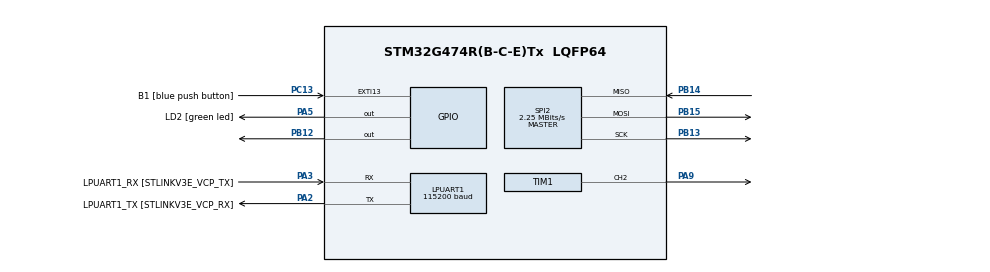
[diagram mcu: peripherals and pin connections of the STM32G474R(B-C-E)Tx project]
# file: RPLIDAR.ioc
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FATFS._MAX_SS=4096
FATFS._USE_LFN=1
LPUART1.BaudRate=115200
LPUART1.WordLength=UART_WORDLENGTH_8B
Mcu.Family=STM32G4
Mcu.Name=STM32G474R(B-C-E)Tx
Mcu.Package=LQFP64
NVIC.EXTI15_10_IRQn=true\:0\:0\:false\:false\:true\:true\:true
NVIC.PriorityGroup=NVIC_PRIORITYGROUP_4
PA13.GPIO_Label=T_SWDIO
PA13.Mode=Serial_Wire
PA13.Signal=SYS_JTMS-SWDIO
PA14.GPIO_Label=T_SWCLK
PA14.Mode=Serial_Wire
PA14.Signal=SYS_JTCK-SWCLK
PA2.GPIO_Label=LPUART1_TX [STLINKV3E_VCP_RX]
PA2.Mode=Asynchronous
PA2.Signal=LPUART1_TX
PA3.GPIO_Label=LPUART1_RX [STLINKV3E_VCP_TX]
PA3.Mode=Asynchronous
PA3.Signal=LPUART1_RX
PA5.GPIO_Label=LD2 [green led]
PA5.Signal=GPIO_Output
PA9.Signal=S_TIM1_CH2
PB12.Signal=GPIO_Output
PB13.Mode=Full_Duplex_Master
PB13.Signal=SPI2_SCK
PB14.Mode=Full_Duplex_Master
PB14.Signal=SPI2_MISO
PB15.Mode=Full_Duplex_Master
PB15.Signal=SPI2_MOSI
PB3.GPIO_Label=T_SWO
PB3.Signal=SYS_JTDO-SWO
PC13.GPIO_Label=B1 [blue push button]
PC13.Signal=GPXTI13
PC14-OSC32_IN.Mode=LSE-External-Oscillator
PC14-OSC32_IN.Signal=RCC_OSC32_IN
PC15-OSC32_OUT.Mode=LSE-External-Oscillator
PC15-OSC32_OUT.Signal=RCC_OSC32_OUT
PF0-OSC_IN.Mode=HSE-External-Oscillator
PF0-OSC_IN.Signal=RCC_OSC_IN
PF1-OSC_OUT.Mode=HSE-External-Oscillator
PF1-OSC_OUT.Signal=RCC_OSC_OUT
ProjectManager.HeapSize=0x200
ProjectManager.StackSize=0x400
ProjectManager.TargetToolchain=STM32CubeIDE
RCC.ADC12Freq_Value=144000000
RCC.ADC345Freq_Value=144000000
RCC.AHBFreq_Value=144000000
RCC.APB1Freq_Value=144000000
RCC.APB1TimFreq_Value=144000000
RCC.APB2Freq_Value=144000000
RCC.APB2TimFreq_Value=144000000
RCC.CortexFreq_Value=144000000
RCC.EXTERNAL_CLOCK_VALUE=12288000
RCC.HCLKFreq_Value=144000000
RCC.HSE_VALUE=24000000
RCC.HSI48_VALUE=48000000
RCC.HSI_VALUE=16000000
RCC.PLLN=18
RCC.RTCClockSelection=RCC_RTCCLKSOURCE_LSE
RCC.SYSCLKFreq_VALUE=144000000
RCC.SYSCLKSource=RCC_SYSCLKSOURCE_PLLCLK
RCC.USBFreq_Value=144000000
RCC.VCOOutputFreq_Value=288000000
SH.S_TIM1_CH2.0=TIM1_CH2,PWM Generation2 CH2
SPI2.BaudRatePrescaler=SPI_BAUDRATEPRESCALER_64
SPI2.CalculateBaudRate=2.25 MBits/s
SPI2.DataSize=SPI_DATASIZE_8BIT
SPI2.Direction=SPI_DIRECTION_2LINES
SPI2.Mode=SPI_MODE_MASTER
SPI2.VirtualType=VM_MASTER
TIM1.AutoReloadPreload=TIM_AUTORELOAD_PRELOAD_ENABLE
TIM1.Channel-PWM\ Generation2\ CH2=TIM_CHANNEL_2
TIM1.PeriodNoDither=5760-1
VP_FATFS_VS_Generic.Mode=User_defined
VP_SYS_VS_DBSignals.Mode=DisableDeadBatterySignals
VP_TIM1_VS_ClockSourceINT.Mode=Internal
board=NUCLEO-G474RE

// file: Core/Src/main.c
/* USER CODE BEGIN Header */
/**
  ******************************************************************************
  * @file           : main.c
  * @brief          : Main program body
  ******************************************************************************
  * @attention
  *
  * Copyright (c) 2022 STMicroelectronics.
  * All rights reserved.
  *
  * This software is licensed under terms that can be found in the LICENSE file
  * in the root directory of this software component.
  * If no LICENSE file comes with this software, it is provided AS-IS.
  *
  ******************************************************************************
  */
/* USER CODE END Header */
#include "main.h"
#include "app_fatfs.h"

/* USER CODE BEGIN Includes */
#include "math.h"
#include "uart_buf_g4.h"
/* USER CODE END Includes */

/* USER CODE BEGIN PD */
/*Comandos*/
#define STOP_RPL            0x25
#define RESET_RPL           0x40
#define SCAN_RPL            0x20
#define EXPRESS_SCAN_RPL    0x82
#define FORCE_SCAN_RPL      0x21
#define GET_INFO_RPL        0x50
#define GET_HEALTH_RPL      0x52
#define GET_SAMPLERATE_RPL  0x59
#define GET_LIDAR_CONF_RPL  0x84
/*StarFlags*/
#define START_FLAG_1         0xA5
#define START_FLAG_2         0x5A
/*Tamaños del buffer*/
#define  RxBuf_SIZE 		10
#define  MainBuf_SIZE 		(2<<14)//13->8192 14->16384 16->65536
#define precision 6  //precision for decimal digits
/* USER CODE END PD */

UART_HandleTypeDef hlpuart1;

SPI_HandleTypeDef hspi2;

TIM_HandleTypeDef htim1;

/* USER CODE BEGIN PV */
__IO ITStatus UserButtonStatus = 0;  /* set to 1 after User Button interrupt  */
uint8_t RxBuf[RxBuf_SIZE];
uint8_t MainBuf[MainBuf_SIZE];
const uint8_t STOP_REQUEST[2]={START_FLAG_1,STOP_RPL};
const uint8_t RESET_REQUEST[2]={START_FLAG_1,RESET_RPL};
const uint8_t SCAN_REQUEST[2]={START_FLAG_1,SCAN_RPL};
const uint8_t SCAN_DESCRIPTOR[7]={START_FLAG_1,START_FLAG_2,0x05,0x00,0x00,0x40,0x81};
const uint8_t GET_HEALTH_REQUEST[2]={START_FLAG_1,GET_HEALTH_RPL};
const uint8_t GET_HEALTH_DESCRIPTOR[7]={START_FLAG_1,START_FLAG_2,0x03,0x00,0x00,0x00,0x06};
const uint8_t GET_INFO_REQUEST[2]={START_FLAG_1,GET_INFO_RPL};
const uint8_t GET_INFO_DESCRIPTOR[7]={START_FLAG_1,START_FLAG_2,0x4,0x00,0x00,0x00,0x04};
const uint8_t EXPRESS_SCAN_REQUEST[7]={START_FLAG_1,EXPRESS_SCAN_RPL};

const uint8_t FORCE_SCAN_REQUEST[7]={START_FLAG_1,FORCE_SCAN_RPL};

/* USER CODE END PV */

void SystemClock_Config(void);
static void MX_GPIO_Init(void);
static void MX_LPUART1_UART_Init(void);
static void MX_SPI2_Init(void);
static void MX_TIM1_Init(void);
/* USER CODE BEGIN PFP */
void HAL_GPIO_EXTI_Callback(uint16_t GPIO_Pin)
{
  if (GPIO_Pin == GPIO_PIN_13)
  {
    UserButtonStatus = 1;
  }
}
uint8_t  BinToAsc(uint8_t  BinValue)
{
    BinValue &= 0x0F;
    if(BinValue > 9) BinValue += 7;
    return(BinValue + '0');
}
// Reverses a string 'str' of length 'len'
void reverse(char* str, int len)
{
    int i = 0, j = len - 1, temp;
    while (i < j) {
        temp = str[i];
        str[i] = str[j];
        str[j] = temp;
        i++;
        j--;
    }
}
// Converts a given integer x to string str[].
// d is the number of digits required in the output.
// If d is more than the number of digits in x,
// then 0s are added at the beginning.
int intToStr(int x, char str[], int d)
{
    int i = 0;
    while (x) {
        str[i++] = (x % 10) + '0';
        x = x / 10;
    }
    // If number of digits required is more, then
    // add 0s at the beginning
    while (i < d)
        str[i++] = '0';

    reverse(str, i);
    str[i] = '\0';
    return i;
}
// Converts a floating-point/double number to a string.
void ftoa(float n, char* res, int beforepoint,int afterpoint)
{
    // Extract integer part
    int ipart = (int)n;

    // Extract floating part
    float fpart = n - (float)ipart;

    // convert integer part to string
    int i = intToStr(ipart, res, beforepoint);

    // check for display option after point
    if (afterpoint != 0) {
        res[i] = '.'; // add dot

        // Get the value of fraction part upto given no.
        // of points after dot. The third parameter
        // is needed to handle cases like 233.007
        fpart = fpart * (float)(pow(10, afterpoint));

        intToStr((int)fpart, res + i + 1, afterpoint);
    }
}
void float_to_char(float f, char *p) {
	int a,b,c,k,l=0,m,i=0;
	// check for negetive float
	if(f<0.0)
	{
		p[i++]='-';
		f*=-1;
	}
	a=f;	// extracting whole number
	f-=a;	// extracting decimal part
	k = precision;
	// number of digits in whole number
	while(k>-1)
	{
		l = pow(10,k);
		m = a/l;
		if(m>0)
		{
			break;
		}
	k--;
	}
	// number of digits in whole number are k+1
	/*
	extracting most significant digit i.e. right most digit , and concatenating to string
	obtained as quotient by dividing number by 10^k where k = (number of digit -1)
	*/
	for(l=k+1;l>0;l--)
	{
		b = pow(10,l-1);
		c = a/b;
		p[i++]=c+48;
		a%=b;
	}
	p[i++] = '.';
	/* extracting decimal digits till precision */
	for(l=0;l<precision;l++)
	{
		f*=10.0;
		b = f;
		p[i++]=b+48;
		f-=b;
	}
	p[i]='\0';
}
void printf_pkt(uint8_t * cmd, uint8_t size){
	char  ascii_chars[size*3];
	for (int i=0;i<size;i++){
		ascii_chars[3*i]=(char)BinToAsc(cmd[i]>>4);
		ascii_chars[3*i+1]=(char)BinToAsc(cmd[i]);
		ascii_chars[3*i+2]='-';
	}
	ascii_chars[3*size-1]=0;
	LPUART1buf_puts(ascii_chars);
	LPUART1buf_puts((char *) "\n\r");
}
void printf_cartesian_data(uint8_t* pkt){
	char S,notS,C;
	//chat quality;
	uint16_t temp;
	float angle,distance,x,y;
	char ascii_chars[30];
	/****Decodificamos el checkbit****/
	C=pkt[1]&0x01;
	/****Decodificamos la bandera Flag****/
	S=pkt[0]&0x01;
	notS=(pkt[0]>>1)&0x01;
	if ((S^notS)&&(C)){
		/****Decodificamos el Angle****/
		//Desplazamos los bits
		temp=(pkt[1]>>1)&0x7F;
		temp|=(pkt[2]<<7);
		angle=(float)temp/64.0;
		angle=angle*M_PI/180.0;
		/****Decodificamos la distancia****/
		//Desplazamos los bits
		temp=pkt[3];
		temp|=(pkt[4]<<8);
		distance=(float)temp/4.0;
		//Procedemos a convertir en coordenadas cartesianas
		x=distance*cosf(angle+M_PI_2);
		y=distance*sinf(angle+M_PI_2);
		//Procedemos a enviarlo por el puerto serial
		LPUART1buf_puts((char*)"[");
		float_to_char(x,ascii_chars);
		LPUART1buf_puts(ascii_chars);
		LPUART1buf_puts((char*)",");
		float_to_char(y,ascii_chars);
		LPUART1buf_puts(ascii_chars);
	}else{
		LPUART1buf_puts((char*)"[Inf,Inf");
	}
	//Imprimos una nueva línea
	LPUART1buf_puts((char*)"]\n\r");
}
void printf_polar_data(uint8_t* pkt){
	char S,notS,C;
	//chat quality;
	uint16_t angle,distance;
	float result;
	char ascii_chars[30];
	/****Decodificamos el checkbit****/
	C=pkt[1]&0x01;
	/****Decodificamos la bandera Flag****/
	S=pkt[0]&0x01;
	notS=(pkt[0]>>1)&0x01;
	if ((S^notS)&&(C)){
		/****Decodificamos el Angle****/
		LPUART1buf_puts((char*)"[");
		//Desplazamos los bits
		angle=(pkt[1]>>1)&0x7F;
		angle|=(pkt[2]<<7);
		//Procedemos a convertir el halfword en ascii
		result=(float)angle/64.0;
		ftoa(result,ascii_chars,3,3);
		LPUART1buf_puts(ascii_chars);
		/****Decodificamos la distancia****/
		LPUART1buf_puts((char*)",");
		//Desplazamos los bits
		distance=pkt[3];
		distance|=(pkt[4]<<8);
		//Procedemos a convertir la distancia
		result=(float)distance/4.0;
		ftoa(result,ascii_chars,5,3);
		LPUART1buf_puts(ascii_chars);
	}else{
		LPUART1buf_puts((char*)"[Inf,Inf");
	}
	//Imprimos una nueva línea
	LPUART1buf_puts((char*)"]\n\r");
}

void printf_data_old_version(uint8_t* pkt){
	char S,notS,C,quality;
	uint16_t angle,distance;
	float result;
	char ascii_chars[30];
	/****Decodificamos el checkbit****/
	C=pkt[1]&0x01;
	/****Decodificamos la bandera Flag****/
	S=pkt[0]&0x01;
	notS=(pkt[0]>>1)&0x01;
	if ((S^notS)&&(C)){
		LPUART1buf_puts((char*)"S: ");
		//Convertimos el uint8_t en ascii
		intToStr(S,ascii_chars,1);
		//Transmitimos por el serial
		LPUART1buf_puts(ascii_chars);
		/****Decodificamos el Quality****/
		LPUART1buf_puts((char*)"\tQuality: ");
		//Realizamos el desplazamiento y el bitmasking
		quality=(pkt[1]>>2)&0x3F;
		//Convertimos el uint8_t en ascii
		intToStr((int)quality,ascii_chars,2);
		//Transmitimos por el serial
		LPUART1buf_puts(ascii_chars);
		/****Decodificamos el Angle****/
		LPUART1buf_puts((char*)"\tAngle: ");
		//Desplazamos los bits
		angle=(pkt[1]>>1)&0x7F;
		angle|=(pkt[2]<<7);
		//Procedemos a convertir el halfword en ascii
		result=(float)angle/64.0;
		ftoa(result,ascii_chars,3,3);
		LPUART1buf_puts(ascii_chars);
		/****Decodificamos la distancia****/
		LPUART1buf_puts((char*)"\tDistance: ");
		//Desplazamos los bits
		distance=pkt[3];
		distance|=(pkt[4]<<8);
		//Procedemos a convertir la distancia
		result=(float)distance/4.0;
		ftoa(result,ascii_chars,5,3);
		LPUART1buf_puts(ascii_chars);
	}else{
		LPUART1buf_puts((char*)"Data error");
	}
	//Imprimos una nueva línea
	LPUART1buf_puts((char*)"\n\r");
}
void setMotorDutyCycle(float duty){
	HAL_TIM_PWM_Stop(&htim1, TIM_CHANNEL_2);
	HAL_Delay(3);
	if (duty!=0){
		//El ARR tiene como valor máximo 6799
		TIM1->CCR2 = duty*68;
		HAL_TIM_PWM_Start(&htim1, TIM_CHANNEL_2);
		HAL_Delay(3);

	}
}
void getRPM(float duty){//Revisar, presenta errores de detección y de transmisión al COM
	//Definimos las variables
	uint8_t byte,S,notS,C;
	uint32_t tiempo=0;
	int count=0;
	float velocity;
	//Detenemos el motor y establecemos el dutycycle
	HAL_TIM_PWM_Stop(&htim1, TIM_CHANNEL_2);
	HAL_Delay(3);
	TIM1->CCR2 = (uint32_t)(duty*68);//El ARR tiene como valor máximo 6799
	HAL_TIM_PWM_Start(&htim1, TIM_CHANNEL_2);
	//Enviamos el comando por uart
	UART1buf_flushRx();
	UART1buf_putn(SCAN_REQUEST,2);
	//Comenzamos a recibir los valores y lo escribimos en el buffer principal.
	for(unsigned int i=0;i<7;i++){
		while(UART1buf_peek()<0);
		UART1buf_getc();
	}
	for(unsigned int i=0;i<1500;i++){
		while(UART1buf_peek()<0);
		byte=UART1buf_getc();
		/****Decodificamos la bandera Flag****/
		S=byte&0x01;
		if (S){
			notS=(byte>>1)&0x01;
			if(notS==0){
				tiempo=tiempo-HAL_GetTick();
				count++;
			}
		}
		for(unsigned int j=0;j<4;j++){
			while(UART1buf_peek()<0);
			UART1buf_getc();
		}
	}
	//Detenemos la trama del SCAN
	UART1buf_putn(STOP_REQUEST, 2);
	UART1buf_flushRx();
	//Calculamos la velocidad
	velocity=60000.0/(float)tiempo;
	char ascii_chars[10];
	//Procedemos a convertir el float en ascii
	ftoa(velocity,ascii_chars,4,3);
	//Imprimimos en pantalla el resultado
	if(count==0){
		LPUART1buf_puts((char*)"Error");
	}else{
		LPUART1buf_puts((char*)"Velocidad: ");
		LPUART1buf_puts(ascii_chars);
	}
	//Imprimos una nueva línea
	LPUART1buf_puts((char*)"\n\r");
}
void SEND_STOP_REQUEST(){
	//Enviamos el comando por uart
	setMotorDutyCycle(0);
	UART1buf_putn(STOP_REQUEST,2);
	//Delay >2ms para poder enviar otro request
	HAL_Delay(2);
}
void SEND_RESET_REQUEST(){
	//Enviamos el comando por uart
	UART1buf_putn(RESET_REQUEST,2);
	//Esperamos a recibir la data basura
	while(UART1buf_peek()<0);
	//Delay >20ms para poder recibir toda la data basura
	HAL_Delay(50);
	//Limpiamos la data basura
	UART1buf_flushRx();
}
void SEND_SCAN_REQUEST(){
	char C;
	//Encendemos el motor
	setMotorDutyCycle(60);
	//Limpiamos el buffer de Recepción
	UART1buf_flushRx();
	//Enviamos el comando por uart
	UART1buf_putn(SCAN_REQUEST,2);
	//Comenzamos a recibir los primeros 7 valores y verificamos si hay error
	for (int i=0;i<7;i++){
		while(UART1buf_peek()<0);
		if (SCAN_DESCRIPTOR[i]!=UART1buf_getc()){
			LPUART1buf_puts((char*)"Error\nA5-5A-05-00-00-40-81\n\r");
			//Enviar nuevamente el comando

			//Analizar si está en protección
			while(1);
		}
	}
	//Esperamos a que sea un nuevo Scan con la bandera S
	//y que la data sea correcta con los check bits
	//esto con el fin de poder obtener como el primer indice el primer Scan
	while(1){
		while(UART1buf_peek()<0);
		/****Decodificamos la bandera Flag****/
		if ((UART1buf_peek()&0x03)==(0x01)){
			MainBuf[0]=UART1buf_getc();
			/****Decodificamos el checkbit****/
			while(UART1buf_peek()<0);
			C=UART1buf_peek()&0x01;
			MainBuf[1]=UART1buf_getc();
			while(UART1buf_peek()<0);
			MainBuf[2]=UART1buf_getc();
			while(UART1buf_peek()<0);
			MainBuf[3]=UART1buf_getc();
			while(UART1buf_peek()<0);
			MainBuf[4]=UART1buf_getc();
			if(C){
				break;
			}
		}else{
			for (int i=0;i<4;i++){
				UART1buf_getc();
				while(UART1buf_peek()<0);
			}
			UART1buf_getc();
		}
	}
	//Escribimos en el buffer principal.
	for(unsigned int i=5;i<1800*5;i++){
		while(UART1buf_peek()<0);
		MainBuf[i]=UART1buf_getc();
	}
	//Detenemos la trama del SCAN
	UART1buf_putn(STOP_REQUEST, 2);
	setMotorDutyCycle(0);
	HAL_Delay(2);
	UART1buf_flushRx();
	//Enviamos los valores escaneados
	for(int i=0;i<1800;i++){
		//Enviamos la data cruda en Hexadecimal
		//printf_pkt(&MainBuf[5*i],5);
		//Enviamos la data procesada: [angle,distance]
		printf_cartesian_data(&MainBuf[5*i]);
	}
}
void SEND_EXPRESS_SCAN_REQUEST(){//Por desarrollar
	//Enviamos el comando por uart
	UART1buf_putn(EXPRESS_SCAN_REQUEST,2);
	//Delay >2ms para poder enviar otro request
	HAL_Delay(2);
}
void SEND_FORCE_SCAN_REQUEST(){//Por desarrollar
	//Enviamos el comando por uart
	UART1buf_putn(FORCE_SCAN_REQUEST,2);
	//Delay >2ms para poder enviar otro request
	HAL_Delay(2);
}
void SEND_GET_INFO_REQUEST(){
	uint8_t model,firmware_minor,firmware_major,hardware;
	uint64_t serial_number_lsbytes=0,serial_number_msbytes=0;//dividimos en dos variables de 8bytes
	//Limpiamos el buffer de Recepción
	UART1buf_flushRx();
	//Enviamos el comando por uart
	UART1buf_putn(GET_INFO_REQUEST,2);
	//Comenzamos a recibir los primeros 7 valores y verificamos si hay error
	for (int i=0;i<7;i++){
		while(UART1buf_peek()<0);
		if (GET_HEALTH_DESCRIPTOR[i]!=UART1buf_getc()){
			LPUART1buf_puts((char*)"Error\nA5-5A-05-14-00-00-04\n\r");
			//Enviar nuevamente el comando

			//Analizar si está en protección
			while(1);
		}
	}
	//Obtenemos las variables del response
	while(UART1buf_peek()<0);
	model=UART1buf_getc();
	while(UART1buf_peek()<0);
	firmware_minor=UART1buf_getc();
	while(UART1buf_peek()<0);
	firmware_major=UART1buf_getc();
	while(UART1buf_peek()<0);
	hardware=UART1buf_getc();
	//Los primeros 8bytes del serial number
	for (int i=0;i<8;i++){
		while(UART1buf_peek()<0);
		serial_number_lsbytes|=(UART1buf_getc()<<8*i);
	}
	//Los 8bytes mas significativos del serial number
	for (int i=0;i<8;i++){
			while(UART1buf_peek()<0);
			serial_number_msbytes|=(UART1buf_getc()<<8*i);
		}
	//Analizar que hacer con dichos valores

	//return status;

}
void SEND_GET_HEALTH_REQUEST(){
	uint8_t status;
	uint16_t error_code;
	//Limpiamos el buffer de Recepción
	UART1buf_flushRx();
	//Enviamos el comando por uart
	UART1buf_putn(GET_HEALTH_REQUEST,2);
	//Comenzamos a recibir los primeros 7 valores y verificamos si hay error
	for (int i=0;i<7;i++){
		while(UART1buf_peek()<0);
		if (GET_HEALTH_DESCRIPTOR[i]!=UART1buf_getc()){
			LPUART1buf_puts((char*)"Error\nA5-5A-05-00-00-00-06\n\r");
			//Enviar nuevamente el comando

			//Analizar si está en protección
			while(1);
		}
	}
	//Obtenemos el status y el error code
	while(UART1buf_peek()<0);
	status=UART1buf_getc();
	while(UART1buf_peek()<0);
	error_code=UART1buf_getc();
	while(UART1buf_peek()<0);
	error_code|=(UART1buf_getc()<<8);
	//Analizar que hacer con dichos valores

	//return status;
}
/* USER CODE END PFP */

int main(void)
{

  /* MCU Configuration--------------------------------------------------------*/

  /* Reset of all peripherals, Initializes the Flash interface and the Systick. */
  HAL_Init();

  /* Configure the system clock */
  SystemClock_Config();

  /* Initialize all configured peripherals */
  MX_GPIO_Init();
  MX_LPUART1_UART_Init();
  MX_SPI2_Init();
  MX_TIM1_Init();
  if (MX_FATFS_Init() != APP_OK) {
    Error_Handler();
  }
  /* USER CODE BEGIN 2 */
  LPUART1buf_init(115200,SERIAL_8N1,0);
  UART1buf_init(256000,SERIAL_8N1,0);
  SEND_RESET_REQUEST();
  /* USER CODE END 2 */

  /* Infinite loop */
  /* USER CODE BEGIN WHILE */
  while (1)
  {
	  //HAL_UART_Receive(&huart1, eraser_reg,70 , 4);
	  //Esperamos a que se presione el Boton
	  LPUART1buf_puts((char*)"Comando linea:\n\r");
	  //HAL_UART_Transmit(&hlpuart1, (uint8_t*)"Comando linea:\n\r", 16, 300);
	  while(!HAL_GPIO_ReadPin(GPIOC, GPIO_PIN_13));
	  //Esperamos que se suelte
	  while(HAL_GPIO_ReadPin(GPIOC, GPIO_PIN_13));
	  /*Enviamos el comando GET_HEALTH*/
	  SEND_SCAN_REQUEST();

	  //while (UserButtonStatus == 0);

    /* USER CODE END WHILE */

  }
}

void SystemClock_Config(void)
{
  RCC_OscInitTypeDef RCC_OscInitStruct = {0};
  RCC_ClkInitTypeDef RCC_ClkInitStruct = {0};

  /** Configure the main internal regulator output voltage
  */
  HAL_PWREx_ControlVoltageScaling(PWR_REGULATOR_VOLTAGE_SCALE1_BOOST);
  /** Initializes the RCC Oscillators according to the specified parameters
  * in the RCC_OscInitTypeDef structure.
  */
  RCC_OscInitStruct.OscillatorType = RCC_OSCILLATORTYPE_HSI;
  RCC_OscInitStruct.HSIState = RCC_HSI_ON;
  RCC_OscInitStruct.HSICalibrationValue = RCC_HSICALIBRATION_DEFAULT;
  RCC_OscInitStruct.PLL.PLLState = RCC_PLL_ON;
  RCC_OscInitStruct.PLL.PLLSource = RCC_PLLSOURCE_HSI;
  RCC_OscInitStruct.PLL.PLLM = RCC_PLLM_DIV4;
  RCC_OscInitStruct.PLL.PLLN = 85;
  RCC_OscInitStruct.PLL.PLLP = RCC_PLLP_DIV2;
  RCC_OscInitStruct.PLL.PLLQ = RCC_PLLQ_DIV2;
  RCC_OscInitStruct.PLL.PLLR = RCC_PLLR_DIV2;
  if (HAL_RCC_OscConfig(&RCC_OscInitStruct) != HAL_OK)
  {
    Error_Handler();
  }
  /** Initializes the CPU, AHB and APB buses clocks
  */
  RCC_ClkInitStruct.ClockType = RCC_CLOCKTYPE_HCLK|RCC_CLOCKTYPE_SYSCLK
                              |RCC_CLOCKTYPE_PCLK1|RCC_CLOCKTYPE_PCLK2;
  RCC_ClkInitStruct.SYSCLKSource = RCC_SYSCLKSOURCE_PLLCLK;
  RCC_ClkInitStruct.AHBCLKDivider = RCC_SYSCLK_DIV1;
  RCC_ClkInitStruct.APB1CLKDivider = RCC_HCLK_DIV1;
  RCC_ClkInitStruct.APB2CLKDivider = RCC_HCLK_DIV1;

  if (HAL_RCC_ClockConfig(&RCC_ClkInitStruct, FLASH_LATENCY_4) != HAL_OK)
  {
    Error_Handler();
  }
}

static void MX_LPUART1_UART_Init(void)
{

  hlpuart1.Instance = LPUART1;
  hlpuart1.Init.BaudRate = 115200;
  hlpuart1.Init.WordLength = UART_WORDLENGTH_8B;
  hlpuart1.Init.StopBits = UART_STOPBITS_1;
  hlpuart1.Init.Parity = UART_PARITY_NONE;
  hlpuart1.Init.Mode = UART_MODE_TX_RX;
  hlpuart1.Init.HwFlowCtl = UART_HWCONTROL_NONE;
  hlpuart1.Init.OneBitSampling = UART_ONE_BIT_SAMPLE_DISABLE;
  hlpuart1.Init.ClockPrescaler = UART_PRESCALER_DIV1;
  hlpuart1.AdvancedInit.AdvFeatureInit = UART_ADVFEATURE_NO_INIT;
  if (HAL_UART_Init(&hlpuart1) != HAL_OK)
  {
    Error_Handler();
  }
  if (HAL_UARTEx_SetTxFifoThreshold(&hlpuart1, UART_TXFIFO_THRESHOLD_1_8) != HAL_OK)
  {
    Error_Handler();
  }
  if (HAL_UARTEx_SetRxFifoThreshold(&hlpuart1, UART_RXFIFO_THRESHOLD_1_8) != HAL_OK)
  {
    Error_Handler();
  }
  if (HAL_UARTEx_DisableFifoMode(&hlpuart1) != HAL_OK)
  {
    Error_Handler();
  }

}

static void MX_SPI2_Init(void)
{

  /* SPI2 parameter configuration*/
  hspi2.Instance = SPI2;
  hspi2.Init.Mode = SPI_MODE_MASTER;
  hspi2.Init.Direction = SPI_DIRECTION_2LINES;
  hspi2.Init.DataSize = SPI_DATASIZE_8BIT;
  hspi2.Init.CLKPolarity = SPI_POLARITY_LOW;
  hspi2.Init.CLKPhase = SPI_PHASE_1EDGE;
  hspi2.Init.NSS = SPI_NSS_SOFT;
  hspi2.Init.BaudRatePrescaler = SPI_BAUDRATEPRESCALER_16;
  hspi2.Init.FirstBit = SPI_FIRSTBIT_MSB;
  hspi2.Init.TIMode = SPI_TIMODE_DISABLE;
  hspi2.Init.CRCCalculation = SPI_CRCCALCULATION_DISABLE;
  hspi2.Init.CRCPolynomial = 7;
  hspi2.Init.CRCLength = SPI_CRC_LENGTH_DATASIZE;
  hspi2.Init.NSSPMode = SPI_NSS_PULSE_ENABLE;
  if (HAL_SPI_Init(&hspi2) != HAL_OK)
  {
    Error_Handler();
  }

}

static void MX_TIM1_Init(void)
{

  TIM_ClockConfigTypeDef sClockSourceConfig = {0};
  TIM_MasterConfigTypeDef sMasterConfig = {0};
  TIM_OC_InitTypeDef sConfigOC = {0};
  TIM_BreakDeadTimeConfigTypeDef sBreakDeadTimeConfig = {0};

  htim1.Instance = TIM1;
  htim1.Init.Prescaler = 0;
  htim1.Init.CounterMode = TIM_COUNTERMODE_UP;
  htim1.Init.Period = 6799;
  htim1.Init.ClockDivision = TIM_CLOCKDIVISION_DIV1;
  htim1.Init.RepetitionCounter = 0;
  htim1.Init.AutoReloadPreload = TIM_AUTORELOAD_PRELOAD_ENABLE;
  if (HAL_TIM_Base_Init(&htim1) != HAL_OK)
  {
    Error_Handler();
  }
  sClockSourceConfig.ClockSource = TIM_CLOCKSOURCE_INTERNAL;
  if (HAL_TIM_ConfigClockSource(&htim1, &sClockSourceConfig) != HAL_OK)
  {
    Error_Handler();
  }
  if (HAL_TIM_PWM_Init(&htim1) != HAL_OK)
  {
    Error_Handler();
  }
  sMasterConfig.MasterOutputTrigger = TIM_TRGO_RESET;
  sMasterConfig.MasterOutputTrigger2 = TIM_TRGO2_RESET;
  sMasterConfig.MasterSlaveMode = TIM_MASTERSLAVEMODE_DISABLE;
  if (HAL_TIMEx_MasterConfigSynchronization(&htim1, &sMasterConfig) != HAL_OK)
  {
    Error_Handler();
  }
  sConfigOC.OCMode = TIM_OCMODE_PWM1;
  sConfigOC.Pulse = 0;
  sConfigOC.OCPolarity = TIM_OCPOLARITY_HIGH;
  sConfigOC.OCNPolarity = TIM_OCNPOLARITY_HIGH;
  sConfigOC.OCFastMode = TIM_OCFAST_DISABLE;
  sConfigOC.OCIdleState = TIM_OCIDLESTATE_RESET;
  sConfigOC.OCNIdleState = TIM_OCNIDLESTATE_RESET;
  if (HAL_TIM_PWM_ConfigChannel(&htim1, &sConfigOC, TIM_CHANNEL_2) != HAL_OK)
  {
    Error_Handler();
  }
  sBreakDeadTimeConfig.OffStateRunMode = TIM_OSSR_DISABLE;
  sBreakDeadTimeConfig.OffStateIDLEMode = TIM_OSSI_DISABLE;
  sBreakDeadTimeConfig.LockLevel = TIM_LOCKLEVEL_OFF;
  sBreakDeadTimeConfig.DeadTime = 0;
  sBreakDeadTimeConfig.BreakState = TIM_BREAK_DISABLE;
  sBreakDeadTimeConfig.BreakPolarity = TIM_BREAKPOLARITY_HIGH;
  sBreakDeadTimeConfig.BreakFilter = 0;
  sBreakDeadTimeConfig.BreakAFMode = TIM_BREAK_AFMODE_INPUT;
  sBreakDeadTimeConfig.Break2State = TIM_BREAK2_DISABLE;
  sBreakDeadTimeConfig.Break2Polarity = TIM_BREAK2POLARITY_HIGH;
  sBreakDeadTimeConfig.Break2Filter = 0;
  sBreakDeadTimeConfig.Break2AFMode = TIM_BREAK_AFMODE_INPUT;
  sBreakDeadTimeConfig.AutomaticOutput = TIM_AUTOMATICOUTPUT_DISABLE;
  if (HAL_TIMEx_ConfigBreakDeadTime(&htim1, &sBreakDeadTimeConfig) != HAL_OK)
  {
    Error_Handler();
  }
  HAL_TIM_MspPostInit(&htim1);

}

static void MX_GPIO_Init(void)
{
  GPIO_InitTypeDef GPIO_InitStruct = {0};

  /* GPIO Ports Clock Enable */
  __HAL_RCC_GPIOC_CLK_ENABLE();
  __HAL_RCC_GPIOF_CLK_ENABLE();
  __HAL_RCC_GPIOA_CLK_ENABLE();
  __HAL_RCC_GPIOB_CLK_ENABLE();

  /*Configure GPIO pin Output Level */
  HAL_GPIO_WritePin(LD2_GPIO_Port, LD2_Pin, GPIO_PIN_RESET);

  /*Configure GPIO pin Output Level */
  HAL_GPIO_WritePin(GPIOB, GPIO_PIN_12, GPIO_PIN_RESET);

  /*Configure GPIO pin : B1_Pin */
  GPIO_InitStruct.Pin = B1_Pin;
  GPIO_InitStruct.Mode = GPIO_MODE_IT_RISING;
  GPIO_InitStruct.Pull = GPIO_NOPULL;
  HAL_GPIO_Init(B1_GPIO_Port, &GPIO_InitStruct);

  /*Configure GPIO pin : LD2_Pin */
  GPIO_InitStruct.Pin = LD2_Pin;
  GPIO_InitStruct.Mode = GPIO_MODE_OUTPUT_PP;
  GPIO_InitStruct.Pull = GPIO_NOPULL;
  GPIO_InitStruct.Speed = GPIO_SPEED_FREQ_LOW;
  HAL_GPIO_Init(LD2_GPIO_Port, &GPIO_InitStruct);

  /*Configure GPIO pin : PB12 */
  GPIO_InitStruct.Pin = GPIO_PIN_12;
  GPIO_InitStruct.Mode = GPIO_MODE_OUTPUT_PP;
  GPIO_InitStruct.Pull = GPIO_NOPULL;
  GPIO_InitStruct.Speed = GPIO_SPEED_FREQ_LOW;
  HAL_GPIO_Init(GPIOB, &GPIO_InitStruct);

  /* EXTI interrupt init*/
  HAL_NVIC_SetPriority(EXTI15_10_IRQn, 0, 0);
  HAL_NVIC_EnableIRQ(EXTI15_10_IRQn);

}

void Error_Handler(void)
{
  __disable_irq();
  while (1)
  {
  }
}
